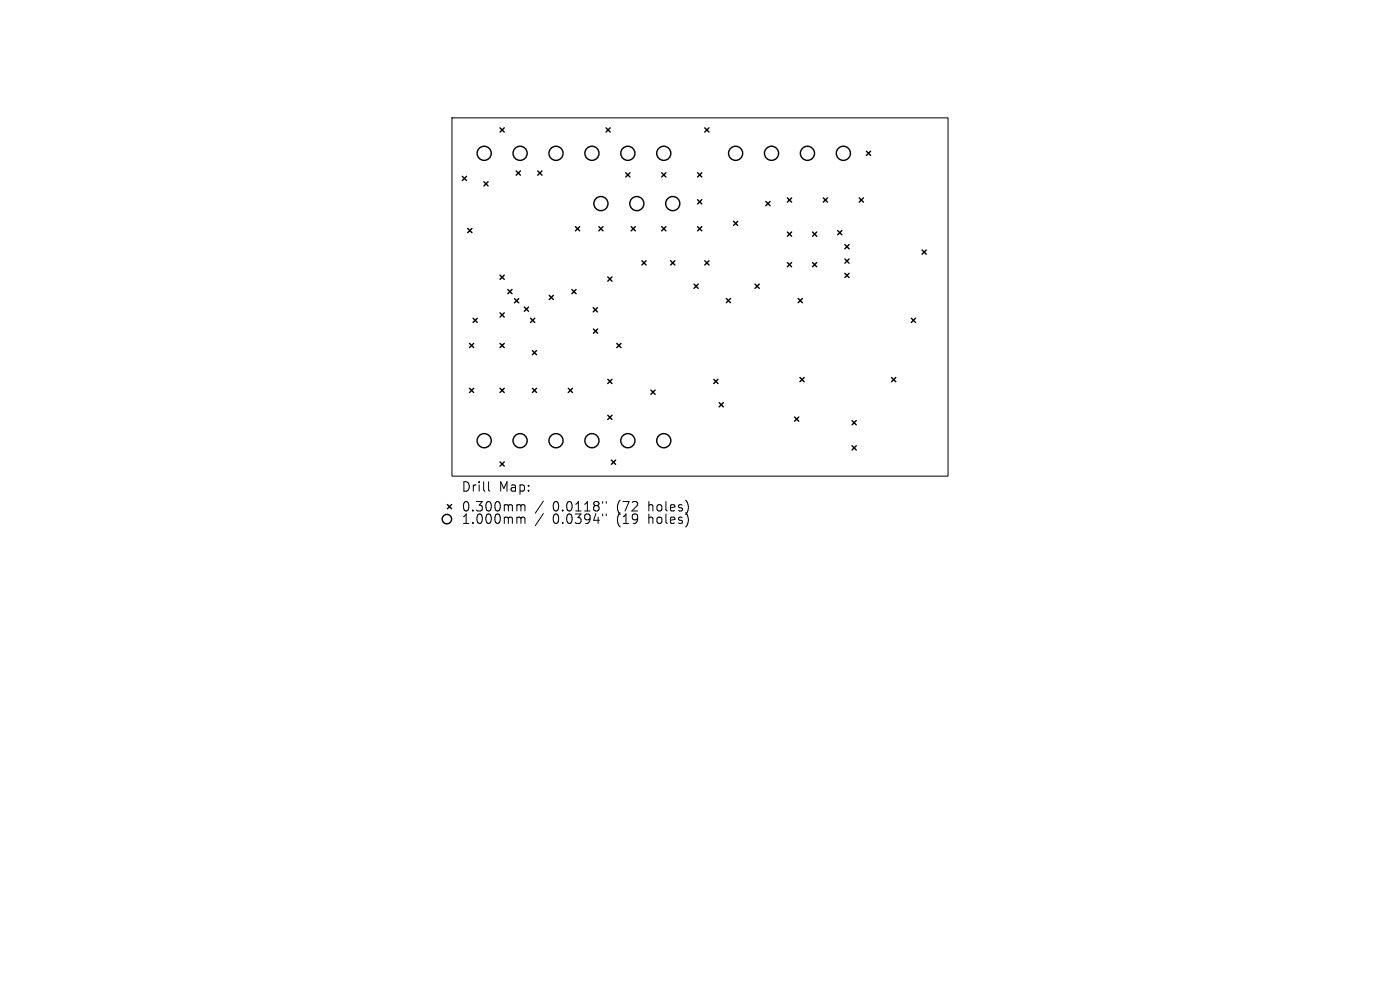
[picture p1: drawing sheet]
<svg xmlns="http://www.w3.org/2000/svg" width="297mm" height="210mm" viewBox="0 0 297 210" stroke-linecap="round" stroke-linejoin="round" font-family="sans-serif">
<defs><g id="words">
<g font-size="2.8">
<text x="97.8" y="104.6">Drill</text>
<text x="105.8" y="104.6">Map:</text>
<text x="97.8" y="108.8">0.300mm</text>
<text x="97.8" y="111.4">1.000mm</text>
<text x="117.3" y="108.8">0.0118&quot;</text>
<text x="117.3" y="111.4">0.0394&quot;</text>
<text x="131" y="108.8">(72</text>
<text x="131" y="111.4">(19</text>
<text x="137.8" y="108.8">holes)</text>
<text x="137.8" y="111.4">holes)</text>
</g>
</g></defs>
<g fill="none" stroke="#000" stroke-width=".21">
<path d="M95.9 25h105.2v76h-105.2zM103.7 102.2v1.7l.2 .3M109.9 107.1h.3l.3 .2M109.9 109.7h.3l.3 .3M110.5 107.3l.3-.2 .5 .1 .1 1.2M110.5 107.3v1.1M110.5 110v1M110.5 110l.3-.3 .5 .1 .1 1.2M115.3 106.3l-1.7 2.6M115.3 108.9l-1.7 2.6M127.8 106.4v.4M127.8 109v.4"/>
<path d="M128.6 106.4v.4M128.6 109v.4"/>
</g>
<g fill="none" stroke="#000" stroke-width=".3">
<path d="M98.1 37.4l.9 .9M99 37.4l-.9 .9M102.6 38.5l.9 .9M103.5 38.5l-.9 .9M106.1 27.1l.9 .9M107 27.1l-.9 .9M109.5 36.3l.9 .9M110.4 36.3l-.9 .9M114.1 36.3l.9 .9M115 36.3l-.9 .9M128.6 27.1l.9 .9M129.5 27.1l-.9 .9"/>
<path d="M132.7 36.6l.9 .9M133.6 36.6l-.9 .9M140.4 36.6l.9 .9M141.3 36.6l-.9 .9M148 36.6l.9 .9M148.9 36.6l-.9 .9M149.5 27.1l.9 .9M150.4 27.1l-.9 .9M183.8 32.1l.9 .9M184.7 32.1l-.9 .9M99.2 48.5l.9 .9M100.1 48.5l-.9 .9"/>
<path d="M106.1 58.4l.9 .9M107 58.4l-.9 .9M122.1 48.1l.9 .9M123 48.1l-.9 .9M127 48.1l.9 .9M127.9 48.1l-.9 .9M128.9 58.7l.9 .9M129.8 58.7l-.9 .9M133.9 48.1l.9 .9M134.8 48.1l-.9 .9M136.2 55.3l.9 .9M137.1 55.3l-.9 .9"/>
<path d="M140.4 48.1l.9 .9M141.3 48.1l-.9 .9M142.3 55.3l.9 .9M143.2 55.3l-.9 .9M148 42.4l.9 .9M148 48.1l.9 .9M148.9 42.4l-.9 .9M148.9 48.1l-.9 .9M149.5 55.3l.9 .9M150.4 55.3l-.9 .9M155.6 46.9l.9 .9M156.5 46.9l-.9 .9"/>
<path d="M162.5 42.7l.9 .9M163.4 42.7l-.9 .9M167 42l.9 .9M167 49.2l.9 .9M167 55.7l.9 .9M167.9 42l-.9 .9M167.9 49.2l-.9 .9M167.9 55.7l-.9 .9M172.4 49.2l.9 .9M172.4 55.7l.9 .9M173.3 49.2l-.9 .9M173.3 55.7l-.9 .9"/>
<path d="M174.7 42l.9 .9M175.6 42l-.9 .9M177.7 48.9l.9 .9M178.6 48.9l-.9 .9M179.2 51.9l.9 .9M179.2 54.9l.9 .9M179.2 58l.9 .9M180.1 51.9l-.9 .9M180.1 54.9l-.9 .9M180.1 58l-.9 .9M182.3 42l.9 .9M183.2 42l-.9 .9"/>
<path d="M195.6 53l.9 .9M196.5 53l-.9 .9M99.6 72.8l.9 .9M100.4 67.5l.9 .9M100.5 72.8l-.9 .9M101.3 67.5l-.9 .9M106.1 66.4l.9 .9M106.1 72.8l.9 .9M107 66.4l-.9 .9M107 72.8l-.9 .9M107.7 61.4l.9 .9M108.6 61.4l-.9 .9"/>
<path d="M109.1 63.3l.9 .9M110 63.3l-.9 .9M111.2 65.1l.9 .9M112.1 65.1l-.9 .9M112.6 67.5l.9 .9M112.9 74.4l.9 .9M113.5 67.5l-.9 .9M113.8 74.4l-.9 .9M116.5 62.6l.9 .9M117.4 62.6l-.9 .9M121.3 61.4l.9 .9M122.2 61.4l-.9 .9"/>
<path d="M125.8 65.3l.9 .9M125.9 69.8l.9 .9M126.7 65.3l-.9 .9M126.8 69.8l-.9 .9M130.8 72.8l.9 .9M131.7 72.8l-.9 .9M147.2 60.3l.9 .9M148.1 60.3l-.9 .9M154.1 63.3l.9 .9M155 63.3l-.9 .9M160.2 60.3l.9 .9M161.1 60.3l-.9 .9"/>
<path d="M169.3 63.3l.9 .9M170.2 63.3l-.9 .9M193.3 67.5l.9 .9M194.2 67.5l-.9 .9M99.6 82.4l.9 .9M100.5 82.4l-.9 .9M106.1 82.4l.9 .9M106.1 98l.9 .9M107 82.4l-.9 .9M107 98l-.9 .9M112.9 82.4l.9 .9M113.8 82.4l-.9 .9"/>
<path d="M120.6 82.4l.9 .9M121.5 82.4l-.9 .9M128.9 80.5l.9 .9M128.9 88.1l.9 .9M129.7 97.6l.9 .9M129.8 80.5l-.9 .9M129.8 88.1l-.9 .9M130.6 97.6l-.9 .9M138.1 82.7l.9 .9M139 82.7l-.9 .9M151.4 80.5l.9 .9M152.3 80.5l-.9 .9"/>
<path d="M152.6 85.4l.9 .9M153.5 85.4l-.9 .9M168.6 88.5l.9 .9M169.5 88.5l-.9 .9M169.7 80.1l.9 .9M170.6 80.1l-.9 .9M180.8 89.2l.9 .9M180.8 94.6l.9 .9M181.7 89.2l-.9 .9M181.7 94.6l-.9 .9M189.1 80.1l.9 .9M190 80.1l-.9 .9"/>
<path d="M94.9 107l.9 .9M95.8 107l-.9 .9"/>
<circle cx="102.7" cy="32.5" r="1.5"/>
<circle cx="110.3" cy="32.5" r="1.5"/>
<circle cx="118" cy="32.5" r="1.5"/>
<circle cx="125.6" cy="32.5" r="1.5"/>
<circle cx="133.2" cy="32.5" r="1.5"/>
<circle cx="140.8" cy="32.5" r="1.5"/>
<circle cx="156.1" cy="32.5" r="1.5"/>
<circle cx="163.7" cy="32.5" r="1.5"/>
<circle cx="171.3" cy="32.5" r="1.5"/>
<circle cx="178.9" cy="32.5" r="1.5"/>
<circle cx="127.5" cy="43.2" r="1.5"/>
<circle cx="135.1" cy="43.2" r="1.5"/>
<circle cx="142.7" cy="43.2" r="1.5"/>
<circle cx="102.7" cy="93.5" r="1.5"/>
<circle cx="110.3" cy="93.5" r="1.5"/>
<circle cx="118" cy="93.5" r="1.5"/>
<circle cx="125.6" cy="93.5" r="1.5"/>
<circle cx="133.2" cy="93.5" r="1.5"/>
<circle cx="140.8" cy="93.5" r="1.5"/>
<circle cx="94.8" cy="110.1" r="1"/>
</g>
<use href="#words"/>
</svg>
